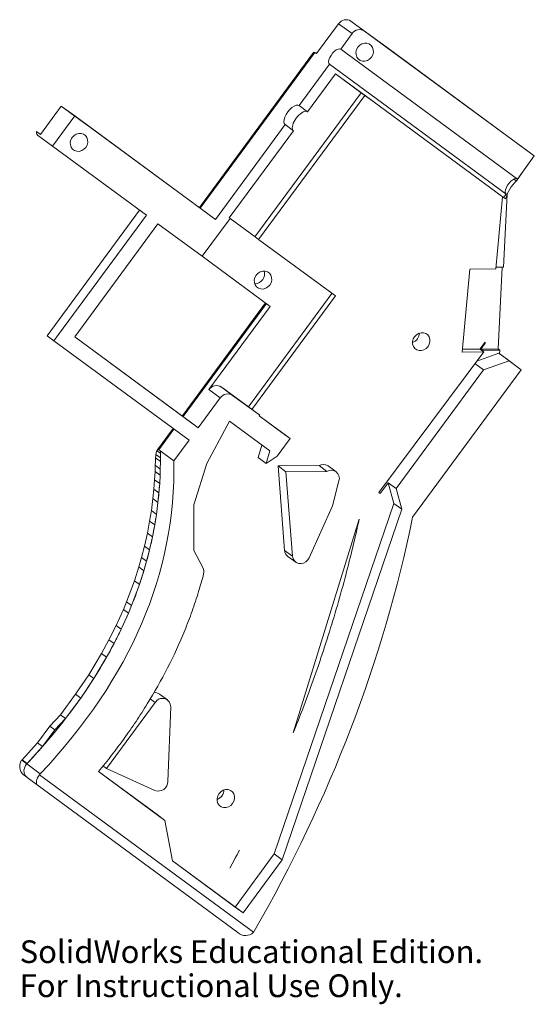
# Model space of a CAD drawing. Units: millimetres. Extents: x -2 to 107, y -186 to 24.
import ezdxf

# ---------------------------------------------------------------- set-up
doc = ezdxf.new("R2010")
doc.units = ezdxf.units.MM
doc.styles.add('SLDTEXTSTYLE0', font='TXT', dxfattribs={"width": 0.7})

msp = doc.modelspace()

# ---------------------------------------------------------------- linework, layer by layer
at = {"color": 7, "linetype": 'Continuous', "lineweight": 15}
for p, q in [((68.17, 23.21), (71.05, 21.09)), ((75.15, 18.08), (68.17, 23.21)), ((65.55, 22.66), (60.86, 16.29)), ((68.42, 20.54), (65.55, 22.66)), ((71.05, 21.09), (107.19, -5.5)), ((65.99, 17.24), (68.42, 20.54)), ((103.58, -10.42), (65.99, 17.24)), ((75.15, 18.08), (74.79, 18.34)), ((103.96, -3.12), (74.79, 18.34)), ((74.79, 18.34), (74.79, 18.34)), ((60.2, 16.5), (35.92, -16.5)), ((60.5, 16.55), (36.09, -16.62)), ((60.86, 16.29), (60.5, 16.55)), ((60.86, 16.29), (60.5, 16.55)), ((57.14, 5.21), (63.62, 14.02)), ((63.62, 14.02), (101.21, -13.64)), ((64.89, 11.98), (58.92, 3.9)), ((64.89, 11.98), (72.81, 6.14)), ((64.89, 11.98), (70.34, 7.95)), ((47.73, -22.71), (70.34, 7.95)), ((71.12, 7.38), (48.51, -23.28)), ((72.81, 6.14), (70.34, 7.95)), ((6.53, 5.13), (2.09, -0.91)), ((9.41, 3.01), (6.53, 5.13)), ((12.31, 0.87), (6.53, 5.13)), ((58.92, 3.9), (57.14, 5.21)), ((100.67, -14.36), (72.81, 6.14)), ((4.66, -3.43), (9.41, 3.01)), ((9.41, 3.01), (39.32, -19)), ((12.31, 0.87), (11.95, 1.14)), ((36.09, -16.62), (11.95, 1.14)), ((39.32, -19), (54.18, 1.18)), ((54.18, 1.18), (55.96, -0.13)), ((2.09, -0.91), (1.25, -0.3)), ((2.09, -0.91), (1.25, -0.3)), ((4.66, -3.43), (1.43, -1.05)), ((55.96, -0.13), (42.28, -18.68)), ((24.63, -18.12), (4.66, -3.43)), ((107.19, -5.5), (103.96, -3.12)), ((103.58, -10.42), (107.19, -5.5)), ((103.4, -10.82), (105.17, -8.26)), ((105.16, -8.26), (105.17, -8.26)), ((105.17, -8.26), (106.01, -7.12)), ((106.01, -7.12), (106.1, -6.99)), ((102.87, -10.44), (103.4, -10.82)), ((99.02, -29.55), (100.42, -14.18)), ((100.67, -14.36), (101.21, -13.64)), ((100.67, -29.18), (101.41, -13.65)), ((100.67, -14.36), (101.07, -14.66)), ((39.32, -19), (36.09, -16.62)), ((23.19, -17.06), (3.52, -43.79)), ((24.63, -18.12), (4.96, -44.85)), ((42.43, -18.79), (36.5, -26.86)), ((42.28, -18.68), (42.43, -18.79)), ((47.79, -22.75), (42.43, -18.8)), ((9.38, -44.02), (27.1, -19.94)), ((36.5, -26.86), (27.1, -19.94)), ((48.51, -23.28), (47.79, -22.75)), ((48.51, -23.28), (64.85, -35.31)), ((50.99, -37.52), (36.5, -26.86)), ((100.67, -29.18), (99.05, -29.2)), ((100.33, -29.19), (99.51, -46.57)), ((91.83, -47.26), (93.44, -29.62)), ((93.44, -29.62), (99.02, -29.55)), ((47.83, -32.71), (47.71, -32.7)), ((64.12, -34.77), (46.34, -58.93)), ((64.85, -35.31), (47.07, -59.47)), ((50, -36.79), (32.28, -60.87)), ((50.17, -36.92), (32.45, -60.99)), ((50.99, -37.52), (37.95, -55.24)), ((3.52, -43.79), (4.96, -44.85)), ((35.68, -63.37), (9.38, -44.02)), ((34.25, -62.32), (9.38, -44.02)), ((4.96, -44.85), (33.74, -66.02)), ((96.74, -45.12), (95.62, -46.62)), ((95.79, -46.62), (96.72, -45.35)), ((96.62, -45.28), (96.72, -45.35)), ((96.72, -45.35), (96.74, -45.12)), ((74.11, -77.14), (96.42, -47.21)), ((96.42, -47.21), (91.83, -47.26)), ((91.88, -46.66), (95.62, -46.62)), ((94.94, -49.19), (99.65, -47.51)), ((95.62, -46.62), (96.42, -47.21)), ((95.79, -46.62), (99.51, -46.57)), ((96.12, -46.86), (95.79, -46.62)), ((96.12, -46.86), (96.06, -46.94)), ((96.12, -46.86), (99.84, -46.82)), ((99.51, -46.57), (99.84, -46.82)), ((99.65, -47.51), (101.81, -49.1)), ((99.65, -47.51), (99.8, -47.62)), ((99.8, -47.62), (99.84, -46.82)), ((94.56, -49.71), (96.37, -51.04)), ((96.37, -51.04), (101.81, -49.1)), ((104.41, -51.02), (101.18, -48.64)), ((101.81, -49.1), (104.41, -51.02)), ((96.37, -51.04), (77.76, -76.32)), ((104.41, -51.02), (81.3, -82.43)), ((40.36, -57.02), (37.95, -55.24)), ((46.34, -58.93), (40.58, -54.69)), ((40.58, -54.69), (42.99, -56.47)), ((42.99, -56.47), (48.76, -60.71)), ((40.36, -57.02), (35.68, -63.37)), ((48.76, -60.71), (46.34, -58.93)), ((48.76, -60.71), (48.66, -60.84)), ((35.68, -63.37), (34.25, -62.32)), ((42.33, -61.98), (37.5, -71.01)), ((50.9, -68.29), (42.33, -61.98)), ((55.24, -65.69), (48.66, -60.84)), ((48.66, -60.84), (53.56, -64.45)), ((30.33, -63.52), (26.95, -68.12)), ((30.5, -63.64), (27.26, -68.04)), ((55.24, -65.69), (53.56, -64.45)), ((33.74, -66.02), (30.5, -70.42)), ((48.4, -69.72), (49.21, -67.05)), ((52.48, -69.45), (55.24, -65.69)), ((26.66, -69.04), (27.64, -69.75)), ((26.87, -68.25), (27.63, -68.81)), ((30.5, -70.42), (27.26, -68.04)), ((27.63, -68.81), (27.62, -68.31)), ((27.64, -69.75), (27.63, -68.81)), ((50.9, -68.29), (50.09, -70.97)), ((26.52, -71.36), (26.54, -70.54)), ((26.58, -69.79), (27.63, -70.57)), ((27.6, -72.16), (27.63, -70.57)), ((27.63, -70.57), (27.64, -69.75)), ((37.5, -71.01), (34.75, -79.75)), ((50.09, -70.97), (48.4, -69.72)), ((50.09, -70.97), (52.48, -69.45)), ((26.38, -74.45), (26.48, -72.67)), ((26.48, -72.67), (26.52, -71.36)), ((26.48, -72.67), (27.56, -73.46)), ((26.52, -71.36), (27.6, -72.16)), ((27.56, -73.46), (27.6, -72.16)), ((61.38, -71.43), (52.65, -71.49)), ((52.65, -71.49), (54.06, -89.49)), ((54.34, -72.74), (52.65, -71.49)), ((63.07, -72.68), (54.34, -72.74)), ((54.34, -72.74), (55.75, -90.74)), ((63.07, -72.68), (61.38, -71.43)), ((65.01, -72.74), (63.32, -71.5)), ((26.23, -76.46), (26.38, -74.45)), ((26.38, -74.45), (27.46, -75.24)), ((27.3, -77.25), (27.46, -75.24)), ((27.46, -75.24), (27.56, -73.46)), ((64.23, -80.01), (65.62, -74.66)), ((74.4, -77.35), (76.07, -75.08)), ((77.29, -79.48), (76.07, -75.08)), ((76.07, -75.08), (77.76, -76.32)), ((26.02, -78.45), (26.23, -76.46)), ((26.23, -76.46), (27.3, -77.25)), ((27.1, -79.25), (27.3, -77.25)), ((74.4, -77.35), (74.11, -77.14)), ((74.11, -77.14), (74.4, -77.35)), ((78.98, -80.72), (77.76, -76.32)), ((25.69, -81.02), (26.02, -78.45)), ((26.02, -78.45), (27.1, -79.25)), ((26.77, -81.82), (27.1, -79.25)), ((51.85, -154.09), (77.29, -79.48)), ((77.29, -79.48), (78.98, -80.72)), ((25.33, -83.25), (25.69, -81.02)), ((25.69, -81.02), (26.77, -81.82)), ((34.75, -79.75), (34.76, -89.51)), ((53.54, -155.33), (78.98, -80.72)), ((59.29, -91.03), (64.23, -80.01)), ((24.85, -85.8), (25.33, -83.25)), ((25.33, -83.25), (26.41, -84.05)), ((26.41, -84.05), (26.77, -81.82)), ((55.89, -128.35), (69.92, -82.83)), ((24.22, -88.6), (24.85, -85.8)), ((24.85, -85.8), (25.93, -86.59)), ((25.93, -86.59), (26.41, -84.05)), ((25.3, -89.39), (25.93, -86.59)), ((23.6, -91), (24.22, -88.6)), ((24.22, -88.6), (25.3, -89.39)), ((24.68, -91.8), (25.3, -89.39)), ((34.76, -89.51), (36.67, -93.13)), ((54.06, -89.49), (55.75, -90.74)), ((23.02, -93), (23.6, -91)), ((23.6, -91), (24.68, -91.8)), ((24.1, -93.8), (24.68, -91.8)), ((54.74, -90.75), (56.43, -91.99)), ((22.07, -95.96), (23.02, -93)), ((23.02, -93), (24.1, -93.8)), ((23.15, -96.75), (24.1, -93.8)), ((20.41, -100.41), (22.07, -95.96)), ((22.07, -95.96), (23.15, -96.75)), ((21.49, -101.2), (23.15, -96.75)), ((19.73, -102.04), (20.41, -100.41)), ((20.41, -100.41), (21.49, -101.2)), ((18.18, -105.48), (19.73, -102.04)), ((19.73, -102.04), (20.81, -102.84)), ((20.81, -102.84), (21.49, -101.2)), ((19.26, -106.27), (20.81, -102.84)), ((16.67, -108.51), (18.18, -105.48)), ((17.75, -109.3), (19.26, -106.27)), ((18.18, -105.48), (19.26, -106.27)), ((15.08, -111.43), (16.67, -108.51)), ((16.67, -108.51), (17.75, -109.3)), ((16.16, -112.22), (17.75, -109.3)), ((12.36, -115.97), (15.08, -111.43)), ((13.44, -116.76), (16.16, -112.22)), ((15.08, -111.43), (16.16, -112.22)), ((9.58, -120.12), (12.36, -115.97)), ((10.66, -120.92), (13.44, -116.76)), ((12.36, -115.97), (13.44, -116.76)), ((6.37, -124.48), (9.58, -120.12)), ((7.45, -125.27), (10.66, -120.92)), ((9.58, -120.12), (10.66, -120.92)), ((26.5, -121.86), (25.43, -121.07)), ((29.13, -121.31), (27.44, -120.07)), ((26.5, -121.86), (16.16, -135.92)), ((29.21, -138.69), (29.81, -122.8)), ((4.09, -126.87), (6.37, -124.48)), ((5.17, -127.66), (7.45, -125.27)), ((6.37, -124.48), (7.45, -125.27)), ((1.47, -130.43), (4.09, -126.87)), ((2.54, -131.23), (5.17, -127.66)), ((4.09, -126.87), (5.17, -127.66)), ((-1.83, -134.07), (1.47, -130.43)), ((-0.76, -134.87), (2.54, -131.23)), ((1.47, -130.43), (2.54, -131.23)), ((-1.89, -134.13), (-1.83, -134.07)), ((-1.89, -134.13), (-0.81, -134.92)), ((-1.83, -134.07), (-0.76, -134.87)), ((-0.82, -134.93), (-0.76, -134.87)), ((-0.82, -134.94), (2.05, -137.05)), ((16.16, -135.92), (15.39, -135.35)), ((16.16, -135.92), (26.45, -140.59)), ((-0.74, -137.81), (-1.1, -137.55)), ((1.42, -139.4), (-0.74, -137.81)), ((1.88, -137.26), (47.45, -170.79)), ((14.44, -136.57), (28.59, -146.98)), ((14.44, -136.57), (26.9, -145.74)), ((44.11, -170.82), (1.42, -139.4)), ((26.9, -145.74), (28.59, -146.98)), ((28.59, -146.98), (30.18, -155.6)), ((42.4, -157.15), (44.42, -153.31)), ((43.51, -165.42), (51.85, -154.09)), ((51.85, -154.09), (53.54, -155.33)), ((30.18, -155.6), (45.2, -166.66)), ((30.18, -155.6), (43.51, -165.42)), ((45.2, -166.66), (53.54, -155.33)), ((43.51, -165.42), (45.2, -166.66))]:
    msp.add_line(p, q, dxfattribs=at)
at = {"color": 7, "linetype": 'Continuous', "lineweight": 15, "flags": 128}
for points in [[(65.99, 17.24), (65.74, 17.32), (65.42, 17.27), (65.04, 17.08), (64.65, 16.78), (64.26, 16.38), (63.93, 15.92), (63.66, 15.44), (63.49, 14.97), (63.42, 14.56), (63.47, 14.23), (63.62, 14.02)], [(72.53, 15.53), (72.81, 16.03), (72.94, 16.57), (72.93, 17.12), (72.77, 17.62), (72.47, 18.04), (72.06, 18.34), (71.57, 18.5), (71.04, 18.51), (70.52, 18.36), (70.04, 18.06), (69.65, 17.65), (69.37, 17.16), (69.24, 16.61), (69.25, 16.07), (69.41, 15.57), (69.71, 15.15), (70.12, 14.85), (70.61, 14.69), (71.14, 14.68), (71.66, 14.83), (72.14, 15.12), (72.53, 15.53)], [(69.56, 17.53), (69.66, 17.65), (69.75, 17.78)], [(60.2, 16.5), (60.24, 16.55), (60.36, 16.6), (60.5, 16.55)], [(57.14, 5.21), (56.86, 5.32), (56.49, 5.29), (56.07, 5.11), (55.61, 4.8), (55.16, 4.37), (54.74, 3.87), (54.39, 3.32), (54.12, 2.76), (53.95, 2.23), (53.91, 1.78), (53.98, 1.42), (54.18, 1.18)], [(55.96, -0.13), (55.82, 0.01), (55.73, 0.21), (55.69, 0.46), (55.71, 0.76), (55.78, 1.09), (55.9, 1.45), (56.07, 1.82), (56.28, 2.19), (56.53, 2.56), (56.8, 2.9), (57.1, 3.21), (57.4, 3.48), (57.7, 3.7), (58, 3.87), (58.28, 3.97), (58.53, 4.01), (58.75, 3.99), (58.92, 3.9)], [(11.73, -3.67), (12.01, -3.17), (12.14, -2.63), (12.13, -2.08), (11.97, -1.58), (11.67, -1.16), (11.26, -0.86), (10.77, -0.7), (10.24, -0.7), (9.72, -0.84), (9.24, -1.14), (8.85, -1.55), (8.57, -2.04), (8.44, -2.59), (8.45, -3.13), (8.61, -3.63), (8.91, -4.05), (9.32, -4.35), (9.81, -4.51), (10.34, -4.52), (10.86, -4.37), (11.34, -4.08), (11.73, -3.67)], [(8.76, -1.67), (8.86, -1.55), (8.95, -1.42)], [(103.58, -10.42), (103.33, -10.33), (103, -10.39), (102.62, -10.57), (102.23, -10.88), (101.85, -11.27), (101.51, -11.73), (101.24, -12.21), (101.07, -12.68), (101, -13.1), (101.05, -13.42), (101.21, -13.64)], [(50.89, -32.98), (50.5, -33.39), (50.02, -33.68), (49.5, -33.83), (48.97, -33.82), (48.48, -33.66), (48.07, -33.36), (47.77, -32.94), (47.61, -32.44), (47.6, -31.9), (47.73, -31.35), (48.01, -30.86), (48.4, -30.45), (48.88, -30.15), (49.4, -30.01), (49.93, -30.01), (50.42, -30.17), (50.83, -30.47), (51.13, -30.89), (51.29, -31.4), (51.3, -31.94), (51.17, -32.48), (50.89, -32.98)], [(81.7, -43.98), (82.09, -43.57), (82.56, -43.27), (83.09, -43.13), (83.62, -43.13), (84.11, -43.29), (84.52, -43.59), (84.81, -44.01), (84.98, -44.51), (84.99, -45.06), (84.85, -45.6), (84.58, -46.1), (84.19, -46.51), (83.71, -46.8), (83.19, -46.95), (82.66, -46.94), (82.17, -46.78), (81.76, -46.48), (81.46, -46.06), (81.3, -45.56), (81.28, -45.02), (81.42, -44.47), (81.7, -43.98)], [(101.18, -48.64), (101.01, -48.51), (100.8, -48.35), (100.54, -48.16), (100.25, -47.95), (99.94, -47.73), (99.8, -47.62)], [(27.26, -68.04), (27.12, -68), (26.99, -68.07), (26.87, -68.25)], [(55.75, -90.74), (55.87, -91.26), (56.14, -91.72), (56.53, -92.06), (57.01, -92.26), (57.54, -92.3), (58.08, -92.19), (58.57, -91.92), (58.99, -91.52), (59.29, -91.03)], [(1.88, -137.26), (1.66, -137.58), (1.48, -137.92), (1.34, -138.24), (1.25, -138.55), (1.22, -138.83), (1.23, -139.08), (1.3, -139.27), (1.42, -139.4)], [(40.11, -141.26), (40.5, -140.85), (40.98, -140.55), (41.5, -140.4), (42.03, -140.41), (42.52, -140.57), (42.93, -140.87), (43.23, -141.29), (43.39, -141.79), (43.4, -142.34), (43.27, -142.88), (42.99, -143.38), (42.6, -143.79), (42.12, -144.08), (41.6, -144.23), (41.07, -144.22), (40.58, -144.06), (40.17, -143.76), (39.87, -143.34), (39.71, -142.84), (39.7, -142.3), (39.83, -141.75), (40.11, -141.26)]]:
    msp.add_lwpolyline(points, dxfattribs=at)
at = {"color": 7, "linetype": 'Continuous', "lineweight": 15}
for centre, radius, start, end in [((67.14, 21.61), 1.9, 57.0005, 146.6463), ((70.01, 19.5), 1.9, 57.0005, 146.6463), ((1.97, -0.53), 0.754, 162.462, 224.2455), ((108.87, -16.77), 8.08, 132.6129, 164.8606), ((47.65, -30.6), 2.12, 274.6569, 16.7675), ((80.6, -43.15), 2.14, 323.2501, 358.544), ((80.58, -43.18), 2.14, 288.7436, 324.0502), ((39.54, -56.29), 1.9, 57.0005, 146.6463), ((41.95, -58.06), 1.9, 57.0005, 146.6463), ((34.67, -70.31), 8.11, 170.9453, 176.3117), ((29.6, -69.4), 2.97, 157.1049, 172.8797), ((38.59, -70.76), 12.05, 175.406, 178.9845), ((62.3, -72.96), 1.78, 55.1575, 121.208), ((63.98, -74.14), 1.72, 342.3212, 121.9748), ((55.76, -89.39), 1.7, 183.5331, 233.0317), ((34.97, -93.99), 1.91, 344.5384, 26.9563), ((26.45, -121.44), 1.68, 54.1258, 97.9102), ((28.04, -122.75), 1.77, 358.6663, 149.8527), ((-0.28, -135.67), 2.23, 136.3328, 143.6531), ((0.1, -135.44), 2.43, 153.4895, 240.3888), ((3.68, -138.58), 2.23, 136.7619, 143.6526), ((27.15, -138.66), 2.06, 250.0503, 359.2147), ((39, -140.46), 2.14, 288.7436, 324.0502), ((39.01, -140.43), 2.14, 323.2501, 358.544), ((45.77, -169.06), 2.42, 226.5752, 314.1444), ((45.65, -169.47), 2.23, 323.6481, 330.1914)]:
    msp.add_arc(centre, radius, start, end, dxfattribs=at)
for points in [[(27.62, -68.31), (27.63, -68.47), (27.63, -68.64), (27.63, -68.81)], [(27.63, -68.81), (27.63, -69.12), (27.64, -69.44), (27.64, -69.75)], [(30.5, -70.42), (30.9, -94.25), (21.42, -116.46), (2.05, -137.05)], [(27.46, -75.24), (27.41, -75.91), (27.36, -76.58), (27.3, -77.25)], [(27.3, -77.25), (27.24, -77.92), (27.18, -78.58), (27.1, -79.25)], [(27.1, -79.25), (27, -80.11), (26.89, -80.96), (26.77, -81.82)], [(26.77, -81.82), (26.66, -82.56), (26.54, -83.31), (26.41, -84.05)], [(47.59, -170.58), (63.75, -142.37), (74.99, -112.99), (81.3, -82.43)], [(26.41, -84.05), (26.26, -84.9), (26.1, -85.75), (25.93, -86.59)], [(25.93, -86.59), (25.73, -87.53), (25.52, -88.46), (25.3, -89.39)], [(25.3, -89.39), (25.1, -90.19), (24.9, -91), (24.68, -91.8)], [(24.68, -91.8), (24.49, -92.46), (24.3, -93.13), (24.1, -93.8)], [(24.1, -93.8), (23.8, -94.79), (23.48, -95.77), (23.15, -96.75)], [(23.15, -96.75), (22.64, -98.24), (22.09, -99.73), (21.49, -101.2)], [(20.81, -102.84), (20.32, -103.99), (19.8, -105.13), (19.26, -106.27)], [(19.26, -106.27), (18.78, -107.29), (18.27, -108.3), (17.75, -109.3)], [(17.75, -109.3), (17.24, -110.28), (16.71, -111.25), (16.16, -112.22)], [(16.16, -112.22), (15.3, -113.74), (14.39, -115.26), (13.44, -116.76)], [(13.44, -116.76), (12.55, -118.16), (11.63, -119.54), (10.66, -120.92)], [(10.66, -120.92), (9.64, -122.38), (8.57, -123.83), (7.45, -125.27)], [(7.45, -125.27), (5.9, -127.27), (4.27, -129.26), (2.54, -131.23)], [(2.54, -131.23), (1.48, -132.45), (0.38, -133.66), (-0.76, -134.87)], [(42.4, -157.15), (43.08, -155.87), (43.76, -154.59), (44.42, -153.31)]]:
    msp.add_open_spline(points, degree=3, dxfattribs=at)
for points, knots in [([(55.89, -128.35), (56.13, -127.75), (56.37, -127.16), (57.43, -124.47), (59.83, -118.19), (62, -111.85), (64.01, -105.47), (64.66, -103.34), (65.9, -99.05), (66.49, -96.9), (68.1, -90.79), (69.06, -86.81), (69.92, -82.83)], [0.2946604, 0.2946604, 0.2946604, 0.2946604, 0.3125, 0.3125, 0.375, 0.5, 0.5, 0.5625, 0.5625, 0.625, 0.625, 0.7403471, 0.7403471, 0.7403471, 0.7403471]), ([(36.81, -94.5), (36.48, -95.75), (36.13, -97), (35.32, -99.64), (34.86, -101.03), (33.87, -103.8), (33.35, -105.17), (30.58, -111.96), (27.9, -117.16), (24.05, -123.42), (23.25, -124.66), (21.61, -127.12), (20.76, -128.33), (18.15, -131.94), (16.33, -134.28), (14.44, -136.57)], [0.3190676, 0.3190676, 0.3190676, 0.3190676, 0.375, 0.375, 0.4375, 0.4375, 0.5, 0.5, 0.75, 0.75, 0.8125, 0.8125, 0.875, 0.875, 1, 1, 1, 1]), ([(-0.81, -134.93), (-1.01, -135.13), (-1.17, -135.38), (-1.37, -135.9), (-1.43, -136.18), (-1.41, -136.73), (-1.35, -136.99), (-1.11, -137.46), (-0.95, -137.66), (-0.74, -137.81)], [0, 0, 0, 0, 0.25, 0.25, 0.5, 0.5, 0.75, 0.75, 1, 1, 1, 1])]:
    msp.add_open_spline(points, degree=3, knots=knots, dxfattribs=at)

# ---------------------------------------------------------------- texts
at = {"color": 7, "linetype": 'Continuous', "char_height": 4.8336, "attachment_point": 1, "style": 'SLDTEXTSTYLE0'}
for s, insert in [('SolidWorks Educational Edition.', (-2.33, -172.5)), ('For Instructional Use Only.', (-2.33, -179.75))]:
    msp.add_mtext(s, dxfattribs=dict(at, insert=insert))

doc.saveas('drawing.dxf')
